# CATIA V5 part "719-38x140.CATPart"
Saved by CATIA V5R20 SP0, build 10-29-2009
Part number: 719-38x140
Definition: NONE
Nomenclature: 719-38x140
Source: Unknown
Description: 719-38x140
Bounding box of the stored display mesh (mm): x 0 to 177, y -25 to 25, z -25 to 25
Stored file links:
  C:\Users\Utente\Desktop\IO LAVORO\3D X SITO CF\X SITO\719\719-38x140.CATPart

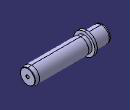
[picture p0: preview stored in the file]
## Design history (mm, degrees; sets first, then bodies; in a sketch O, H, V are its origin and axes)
Body1 "719-38x140" (main body)
  Solid1: solid without history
